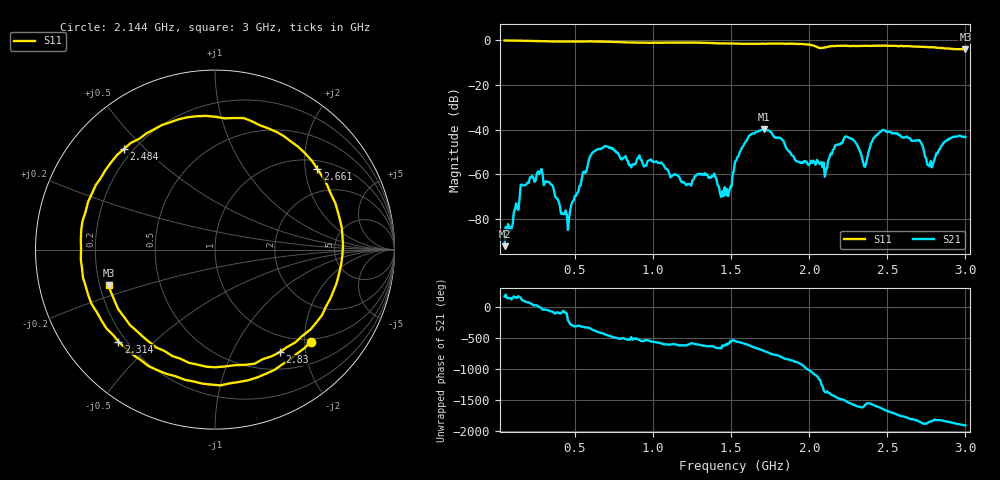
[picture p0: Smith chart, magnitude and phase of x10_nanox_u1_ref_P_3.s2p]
! nanovna_capture.py 2026-10-18T21:00:47+0900
! NanoVNA-F_V2 fw 0.6.0 SN 4A3639384505514B
! cal: load open short thru cal'ed  over 50000000-3000000000 Hz, 201 points
! points 401, avg 4
! S21: port1 = green ~10 mm H loop (flat, tape), port2 = GSM antenna; genuine Nano X u1 at position P (P = user-found best placement), placement 3
# HZ S RI R 50
! S12 and S22 are not measured (written as 0)
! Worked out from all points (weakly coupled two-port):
!   401 points, 50 MHz to 3 GHz, reference 50 ohm
!   highest |S21| = -39.89 dB at 1.709 GHz (marker M1); lowest = -92.2 dB at 50 MHz (marker M2)
!   lowest |S11| = -4.1 dB at 3 GHz (marker M3), VSWR 4.33, Z = 11.8 - j7.74 ohm
!   |S11| at or under -10 dB: nowhere
!   S12 and S22 are empty: the file has one direction only
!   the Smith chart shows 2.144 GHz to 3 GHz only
!   S11 on the Smith chart (normalised r, x): 2.144 GHz: 0.94, -2.14; 2.314 GHz: 0.17, -0.39; 2.484 GHz: 0.17, +0.43; 2.661 GHz: 1.22, +2.32; 2.83 GHz: 0.74, -1.55; 3 GHz: 0.24, -0.15
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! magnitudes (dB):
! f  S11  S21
! 50 MHz  -0.1  -92.2
! 271.2 MHz  -0.4  -60.0
! 448.2 MHz  -0.6  -78.2
! 544.1 MHz  -0.6  -62.0
! 691.6 MHz  -0.6  -47.4
! 1.038 GHz  -1.1  -54.9
! 1.392 GHz  -1.3  -59.7
! 1.451 GHz  -1.4  -69.9
! 1.525 GHz  -1.5  -54.3
! 1.709 GHz  -1.6  -39.9
! 2.019 GHz  -2.2  -55.0
! 2.1 GHz  -3.2  -61.2
! 2.144 GHz  -2.6  -51.1
! 2.24 GHz  -2.5  -43.2
! 2.314 GHz  -2.6  -48.0
! 2.358 GHz  -2.5  -56.7
! 2.484 GHz  -2.4  -40.4
! 2.513 GHz  -2.5  -41.0
! 2.661 GHz  -2.8  -45.1
! 2.771 GHz  -3.1  -56.6
! 2.83 GHz  -3.4  -49.0
! 3 GHz  -4.1  -43.4
